VERSION 5.4 ;
NAMESCASESENSITIVE ON ;
BUSBITCHARS "[]" ;
DIVIDERCHAR "/" ;
UNITS
  DATABASE MICRONS 2000 ;
END UNITS
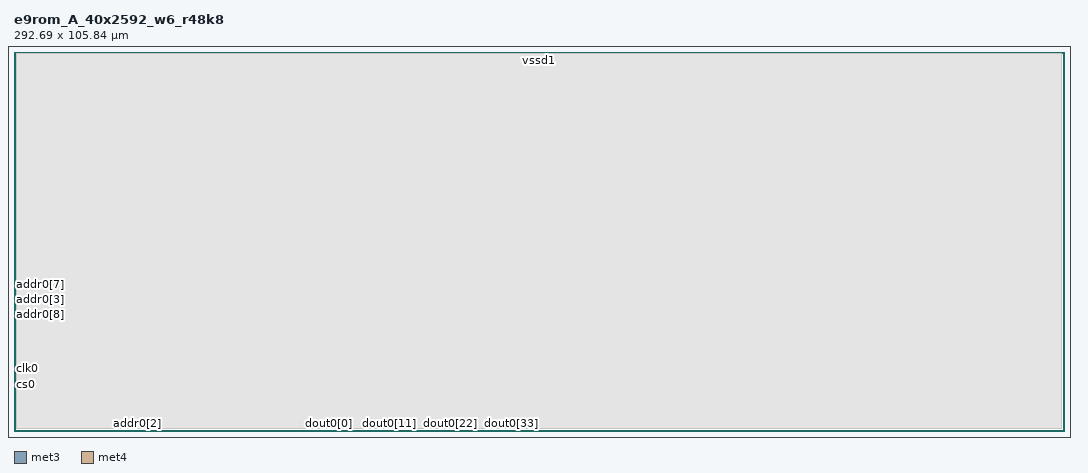
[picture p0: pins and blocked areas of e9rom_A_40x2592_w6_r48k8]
MACRO e9rom_A_40x2592_w6_r48k8
   CLASS BLOCK ;
   SIZE 292.69 BY 105.84 ;
   SYMMETRY X Y R90 ;
   PIN clk0
      DIRECTION INPUT ;
      PORT
         LAYER met3 ;
         RECT  -7.48 17.2 -7.1 17.58 ;
      END
   END clk0
   PIN cs0
      DIRECTION INPUT ;
      PORT
         LAYER met3 ;
         RECT  -7.48 12.675 -7.1 13.055 ;
      END
   END cs0
   PIN addr0[0]
      DIRECTION INPUT ;
      PORT
         LAYER met4 ;
         RECT  30.19 -7.48 30.57 -7.1 ;
      END
   END addr0[0]
   PIN addr0[1]
      DIRECTION INPUT ;
      PORT
         LAYER met4 ;
         RECT  32.23 -7.48 32.61 -7.1 ;
      END
   END addr0[1]
   PIN addr0[2]
      DIRECTION INPUT ;
      PORT
         LAYER met4 ;
         RECT  34.27 -7.48 34.65 -7.1 ;
      END
   END addr0[2]
   PIN addr0[3]
      DIRECTION INPUT ;
      PORT
         LAYER met3 ;
         RECT  -7.48 36.35 -7.1 36.73 ;
      END
   END addr0[3]
   PIN addr0[4]
      DIRECTION INPUT ;
      PORT
         LAYER met3 ;
         RECT  -7.48 37.095 -7.1 37.475 ;
      END
   END addr0[4]
   PIN addr0[5]
      DIRECTION INPUT ;
      PORT
         LAYER met3 ;
         RECT  -7.48 37.785 -7.1 38.165 ;
      END
   END addr0[5]
   PIN addr0[6]
      DIRECTION INPUT ;
      PORT
         LAYER met3 ;
         RECT  -7.48 34.88 -7.1 35.26 ;
      END
   END addr0[6]
   PIN addr0[7]
      DIRECTION INPUT ;
      PORT
         LAYER met3 ;
         RECT  -7.48 38.475 -7.1 38.855 ;
      END
   END addr0[7]
   PIN addr0[8]
      DIRECTION INPUT ;
      PORT
         LAYER met3 ;
         RECT  -7.48 34.19 -7.1 34.57 ;
      END
   END addr0[8]
   PIN dout0[0]
      DIRECTION OUTPUT ;
      PORT
         LAYER met4 ;
         RECT  87.635 -7.48 88.015 -7.1 ;
      END
   END dout0[0]
   PIN dout0[1]
      DIRECTION OUTPUT ;
      PORT
         LAYER met4 ;
         RECT  89.175 -7.48 89.555 -7.1 ;
      END
   END dout0[1]
   PIN dout0[2]
      DIRECTION OUTPUT ;
      PORT
         LAYER met4 ;
         RECT  90.715 -7.48 91.095 -7.1 ;
      END
   END dout0[2]
   PIN dout0[3]
      DIRECTION OUTPUT ;
      PORT
         LAYER met4 ;
         RECT  92.255 -7.48 92.635 -7.1 ;
      END
   END dout0[3]
   PIN dout0[4]
      DIRECTION OUTPUT ;
      PORT
         LAYER met4 ;
         RECT  93.795 -7.48 94.175 -7.1 ;
      END
   END dout0[4]
   PIN dout0[5]
      DIRECTION OUTPUT ;
      PORT
         LAYER met4 ;
         RECT  95.335 -7.48 95.715 -7.1 ;
      END
   END dout0[5]
   PIN dout0[6]
      DIRECTION OUTPUT ;
      PORT
         LAYER met4 ;
         RECT  96.875 -7.48 97.255 -7.1 ;
      END
   END dout0[6]
   PIN dout0[7]
      DIRECTION OUTPUT ;
      PORT
         LAYER met4 ;
         RECT  98.415 -7.48 98.795 -7.1 ;
      END
   END dout0[7]
   PIN dout0[8]
      DIRECTION OUTPUT ;
      PORT
         LAYER met4 ;
         RECT  99.955 -7.48 100.335 -7.1 ;
      END
   END dout0[8]
   PIN dout0[9]
      DIRECTION OUTPUT ;
      PORT
         LAYER met4 ;
         RECT  101.495 -7.48 101.875 -7.1 ;
      END
   END dout0[9]
   PIN dout0[10]
      DIRECTION OUTPUT ;
      PORT
         LAYER met4 ;
         RECT  103.035 -7.48 103.415 -7.1 ;
      END
   END dout0[10]
   PIN dout0[11]
      DIRECTION OUTPUT ;
      PORT
         LAYER met4 ;
         RECT  104.575 -7.48 104.955 -7.1 ;
      END
   END dout0[11]
   PIN dout0[12]
      DIRECTION OUTPUT ;
      PORT
         LAYER met4 ;
         RECT  106.115 -7.48 106.495 -7.1 ;
      END
   END dout0[12]
   PIN dout0[13]
      DIRECTION OUTPUT ;
      PORT
         LAYER met4 ;
         RECT  107.655 -7.48 108.035 -7.1 ;
      END
   END dout0[13]
   PIN dout0[14]
      DIRECTION OUTPUT ;
      PORT
         LAYER met4 ;
         RECT  109.195 -7.48 109.575 -7.1 ;
      END
   END dout0[14]
   PIN dout0[15]
      DIRECTION OUTPUT ;
      PORT
         LAYER met4 ;
         RECT  110.735 -7.48 111.115 -7.1 ;
      END
   END dout0[15]
   PIN dout0[16]
      DIRECTION OUTPUT ;
      PORT
         LAYER met4 ;
         RECT  112.275 -7.48 112.655 -7.1 ;
      END
   END dout0[16]
   PIN dout0[17]
      DIRECTION OUTPUT ;
      PORT
         LAYER met4 ;
         RECT  113.815 -7.48 114.195 -7.1 ;
      END
   END dout0[17]
   PIN dout0[18]
      DIRECTION OUTPUT ;
      PORT
         LAYER met4 ;
         RECT  114.61 -7.48 114.99 -7.1 ;
      END
   END dout0[18]
   PIN dout0[19]
      DIRECTION OUTPUT ;
      PORT
         LAYER met4 ;
         RECT  117.085 -7.48 117.465 -7.1 ;
      END
   END dout0[19]
   PIN dout0[20]
      DIRECTION OUTPUT ;
      PORT
         LAYER met4 ;
         RECT  118.435 -7.48 118.815 -7.1 ;
      END
   END dout0[20]
   PIN dout0[21]
      DIRECTION OUTPUT ;
      PORT
         LAYER met4 ;
         RECT  119.975 -7.48 120.355 -7.1 ;
      END
   END dout0[21]
   PIN dout0[22]
      DIRECTION OUTPUT ;
      PORT
         LAYER met4 ;
         RECT  121.515 -7.48 121.895 -7.1 ;
      END
   END dout0[22]
   PIN dout0[23]
      DIRECTION OUTPUT ;
      PORT
         LAYER met4 ;
         RECT  123.055 -7.48 123.435 -7.1 ;
      END
   END dout0[23]
   PIN dout0[24]
      DIRECTION OUTPUT ;
      PORT
         LAYER met4 ;
         RECT  124.595 -7.48 124.975 -7.1 ;
      END
   END dout0[24]
   PIN dout0[25]
      DIRECTION OUTPUT ;
      PORT
         LAYER met4 ;
         RECT  126.135 -7.48 126.515 -7.1 ;
      END
   END dout0[25]
   PIN dout0[26]
      DIRECTION OUTPUT ;
      PORT
         LAYER met4 ;
         RECT  127.675 -7.48 128.055 -7.1 ;
      END
   END dout0[26]
   PIN dout0[27]
      DIRECTION OUTPUT ;
      PORT
         LAYER met4 ;
         RECT  129.215 -7.48 129.595 -7.1 ;
      END
   END dout0[27]
   PIN dout0[28]
      DIRECTION OUTPUT ;
      PORT
         LAYER met4 ;
         RECT  130.755 -7.48 131.135 -7.1 ;
      END
   END dout0[28]
   PIN dout0[29]
      DIRECTION OUTPUT ;
      PORT
         LAYER met4 ;
         RECT  132.295 -7.48 132.675 -7.1 ;
      END
   END dout0[29]
   PIN dout0[30]
      DIRECTION OUTPUT ;
      PORT
         LAYER met4 ;
         RECT  133.835 -7.48 134.215 -7.1 ;
      END
   END dout0[30]
   PIN dout0[31]
      DIRECTION OUTPUT ;
      PORT
         LAYER met4 ;
         RECT  135.375 -7.48 135.755 -7.1 ;
      END
   END dout0[31]
   PIN dout0[32]
      DIRECTION OUTPUT ;
      PORT
         LAYER met4 ;
         RECT  136.915 -7.48 137.295 -7.1 ;
      END
   END dout0[32]
   PIN dout0[33]
      DIRECTION OUTPUT ;
      PORT
         LAYER met4 ;
         RECT  138.455 -7.48 138.835 -7.1 ;
      END
   END dout0[33]
   PIN dout0[34]
      DIRECTION OUTPUT ;
      PORT
         LAYER met4 ;
         RECT  139.995 -7.48 140.375 -7.1 ;
      END
   END dout0[34]
   PIN dout0[35]
      DIRECTION OUTPUT ;
      PORT
         LAYER met4 ;
         RECT  141.535 -7.48 141.915 -7.1 ;
      END
   END dout0[35]
   PIN dout0[36]
      DIRECTION OUTPUT ;
      PORT
         LAYER met4 ;
         RECT  143.075 -7.48 143.455 -7.1 ;
      END
   END dout0[36]
   PIN dout0[37]
      DIRECTION OUTPUT ;
      PORT
         LAYER met4 ;
         RECT  144.615 -7.48 144.995 -7.1 ;
      END
   END dout0[37]
   PIN dout0[38]
      DIRECTION OUTPUT ;
      PORT
         LAYER met4 ;
         RECT  146.155 -7.48 146.535 -7.1 ;
      END
   END dout0[38]
   PIN dout0[39]
      DIRECTION OUTPUT ;
      PORT
         LAYER met4 ;
         RECT  146.86 -7.48 147.24 -7.1 ;
      END
   END dout0[39]
   PIN vccd1
      DIRECTION INOUT ;
      USE POWER ; 
      SHAPE ABUTMENT ; 
      PORT
         LAYER met4 ;
         RECT  298.43 -7.48 300.17 113.32 ;
         LAYER met3 ;
         RECT  -7.48 111.58 300.17 113.32 ;
         LAYER met3 ;
         RECT  -7.48 -7.48 300.17 -5.74 ;
         LAYER met4 ;
         RECT  -7.48 -7.48 -5.74 113.32 ;
      END
   END vccd1
   PIN vssd1
      DIRECTION INOUT ;
      USE GROUND ; 
      SHAPE ABUTMENT ; 
      PORT
         LAYER met4 ;
         RECT  294.95 -4.0 296.69 109.84 ;
         LAYER met3 ;
         RECT  -4.0 108.1 296.69 109.84 ;
         LAYER met3 ;
         RECT  -4.0 -4.0 296.69 -2.26 ;
         LAYER met4 ;
         RECT  -4.0 -4.0 -2.26 109.84 ;
      END
   END vssd1
   OBS
   LAYER  met1 ;
      RECT  0.62 0.62 292.07 105.22 ;
   LAYER  met2 ;
      RECT  0.62 0.62 292.07 105.22 ;
   LAYER  met3 ;
      RECT  0.62 0.62 292.07 105.22 ;
   LAYER  met4 ;
      RECT  0.62 0.62 292.07 105.22 ;
   END
END    e9rom_A_40x2592_w6_r48k8
END    LIBRARY
